One B-rep face of a CAD part: STEP entity #1589.
In plain terms, the planar face has unit normal (1, 0, 0).
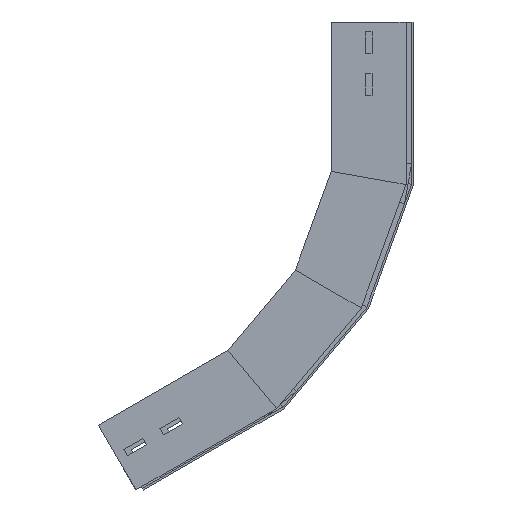
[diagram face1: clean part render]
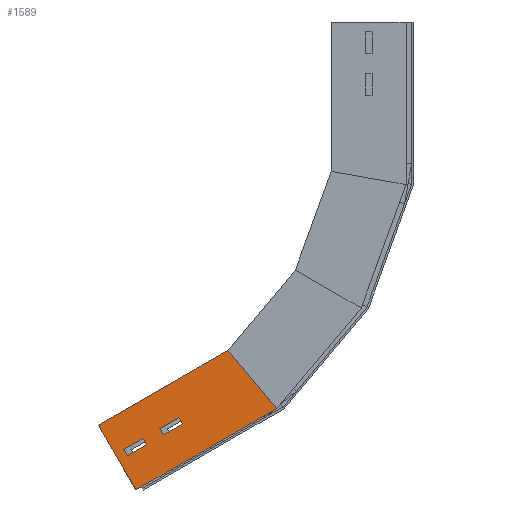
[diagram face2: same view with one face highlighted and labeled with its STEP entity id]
Its self-contained STEP definition (entity closure, numbers rounded to 3 decimals):
#2 = VERTEX_POINT ( 'NONE', #1585 ) ;
#18 = VERTEX_POINT ( 'NONE', #1473 ) ;
#43 = VECTOR ( 'NONE', #1582, 1000. ) ;
#44 = LINE ( 'NONE', #964, #1244 ) ;
#61 = LINE ( 'NONE', #574, #1542 ) ;
#67 = VERTEX_POINT ( 'NONE', #684 ) ;
#82 = LINE ( 'NONE', #198, #102 ) ;
#101 = CARTESIAN_POINT ( 'NONE',  ( 0., 0., 0. ) ) ;
#102 = VECTOR ( 'NONE', #1113, 1000. ) ;
#125 = EDGE_CURVE ( 'NONE', #647, #1373, #150, .T. ) ;
#129 = CARTESIAN_POINT ( 'NONE',  ( 0., 41., -51.505 ) ) ;
#150 = LINE ( 'NONE', #664, #1518 ) ;
#157 = LINE ( 'NONE', #294, #43 ) ;
#158 = VECTOR ( 'NONE', #1565, 1000. ) ;
#182 = CARTESIAN_POINT ( 'NONE',  ( 0., 41., -9.835 ) ) ;
#192 = DIRECTION ( 'NONE',  ( 0., 0., -1. ) ) ;
#196 = CARTESIAN_POINT ( 'NONE',  ( 0., 0., -163. ) ) ;
#198 = CARTESIAN_POINT ( 'NONE',  ( 0., 41., -31.835 ) ) ;
#221 = ORIENTED_EDGE ( 'NONE', *, *, #125, .T. ) ;
#240 = ORIENTED_EDGE ( 'NONE', *, *, #1646, .T. ) ;
#247 = ORIENTED_EDGE ( 'NONE', *, *, #442, .T. ) ;
#248 = EDGE_CURVE ( 'NONE', #67, #1561, #1270, .T. ) ;
#280 = ORIENTED_EDGE ( 'NONE', *, *, #1527, .T. ) ;
#287 = CARTESIAN_POINT ( 'NONE',  ( 0., 0., 0. ) ) ;
#294 = CARTESIAN_POINT ( 'NONE',  ( 0., 41., -51.505 ) ) ;
#314 = AXIS2_PLACEMENT_3D ( 'NONE', #1058, #540, #1076 ) ;
#317 = VERTEX_POINT ( 'NONE', #129 ) ;
#339 = CARTESIAN_POINT ( 'NONE',  ( 0., 41., -73.505 ) ) ;
#348 = DIRECTION ( 'NONE',  ( 0., 1., 0. ) ) ;
#388 = ORIENTED_EDGE ( 'NONE', *, *, #248, .T. ) ;
#400 = EDGE_CURVE ( 'NONE', #18, #814, #1020, .T. ) ;
#413 = EDGE_LOOP ( 'NONE', ( #221, #846, #240, #1072 ) ) ;
#442 = EDGE_CURVE ( 'NONE', #780, #67, #829, .T. ) ;
#476 = VERTEX_POINT ( 'NONE', #196 ) ;
#477 = EDGE_CURVE ( 'NONE', #814, #1327, #61, .T. ) ;
#511 = CARTESIAN_POINT ( 'NONE',  ( 0., 41., -31.835 ) ) ;
#540 = DIRECTION ( 'NONE',  ( -1., 0., 0. ) ) ;
#566 = LINE ( 'NONE', #714, #749 ) ;
#574 = CARTESIAN_POINT ( 'NONE',  ( 0., 75., 0. ) ) ;
#583 = DIRECTION ( 'NONE',  ( 0., 0., -1. ) ) ;
#606 = EDGE_CURVE ( 'NONE', #317, #780, #1043, .T. ) ;
#620 = CARTESIAN_POINT ( 'NONE',  ( 0., 34., -51.505 ) ) ;
#647 = VERTEX_POINT ( 'NONE', #1593 ) ;
#664 = CARTESIAN_POINT ( 'NONE',  ( 0., 41., -9.835 ) ) ;
#681 = FACE_BOUND ( 'NONE', #413, .T. ) ;
#684 = CARTESIAN_POINT ( 'NONE',  ( 0., 34., -73.505 ) ) ;
#714 = CARTESIAN_POINT ( 'NONE',  ( 0., 27.875, -158.085 ) ) ;
#749 = VECTOR ( 'NONE', #1112, 1000. ) ;
#753 = VECTOR ( 'NONE', #348, 1000. ) ;
#780 = VERTEX_POINT ( 'NONE', #339 ) ;
#798 = EDGE_CURVE ( 'NONE', #2, #647, #44, .T. ) ;
#814 = VERTEX_POINT ( 'NONE', #1372 ) ;
#817 = FACE_OUTER_BOUND ( 'NONE', #1051, .T. ) ;
#829 = LINE ( 'NONE', #1221, #1143 ) ;
#846 = ORIENTED_EDGE ( 'NONE', *, *, #869, .T. ) ;
#869 = EDGE_CURVE ( 'NONE', #1373, #926, #984, .T. ) ;
#916 = CARTESIAN_POINT ( 'NONE',  ( 0., 41., -51.505 ) ) ;
#926 = VERTEX_POINT ( 'NONE', #511 ) ;
#964 = CARTESIAN_POINT ( 'NONE',  ( 0., 34., -9.835 ) ) ;
#984 = LINE ( 'NONE', #182, #1570 ) ;
#1020 = LINE ( 'NONE', #101, #753 ) ;
#1043 = LINE ( 'NONE', #916, #1607 ) ;
#1049 = DIRECTION ( 'NONE',  ( 0., 0., -1. ) ) ;
#1051 = EDGE_LOOP ( 'NONE', ( #1305, #1520, #1588, #1184 ) ) ;
#1058 = CARTESIAN_POINT ( 'NONE',  ( 0., 0., 0. ) ) ;
#1060 = VECTOR ( 'NONE', #1049, 1000. ) ;
#1072 = ORIENTED_EDGE ( 'NONE', *, *, #798, .T. ) ;
#1076 = DIRECTION ( 'NONE',  ( 0., 0., 1. ) ) ;
#1101 = DIRECTION ( 'NONE',  ( 0., -1., 0. ) ) ;
#1112 = DIRECTION ( 'NONE',  ( 0., -0.985, -0.174 ) ) ;
#1113 = DIRECTION ( 'NONE',  ( 0., -1., 0. ) ) ;
#1137 = CARTESIAN_POINT ( 'NONE',  ( 0., 41., -9.835 ) ) ;
#1143 = VECTOR ( 'NONE', #1101, 1000. ) ;
#1163 = EDGE_CURVE ( 'NONE', #1327, #476, #566, .T. ) ;
#1177 = ORIENTED_EDGE ( 'NONE', *, *, #606, .T. ) ;
#1184 = ORIENTED_EDGE ( 'NONE', *, *, #1163, .F. ) ;
#1189 = DIRECTION ( 'NONE',  ( 0., 0., 1. ) ) ;
#1194 = DIRECTION ( 'NONE',  ( 0., 1., 0. ) ) ;
#1204 = CARTESIAN_POINT ( 'NONE',  ( 0., 34., -51.505 ) ) ;
#1221 = CARTESIAN_POINT ( 'NONE',  ( 0., 41., -73.505 ) ) ;
#1244 = VECTOR ( 'NONE', #1189, 1000. ) ;
#1260 = CARTESIAN_POINT ( 'NONE',  ( 0., 75., -149.775 ) ) ;
#1270 = LINE ( 'NONE', #620, #158 ) ;
#1289 = DIRECTION ( 'NONE',  ( 0., 0., -1. ) ) ;
#1305 = ORIENTED_EDGE ( 'NONE', *, *, #477, .F. ) ;
#1315 = LINE ( 'NONE', #287, #1060 ) ;
#1327 = VERTEX_POINT ( 'NONE', #1260 ) ;
#1336 = FACE_BOUND ( 'NONE', #1640, .T. ) ;
#1372 = CARTESIAN_POINT ( 'NONE',  ( 0., 75., 0. ) ) ;
#1373 = VERTEX_POINT ( 'NONE', #1137 ) ;
#1451 = PLANE ( 'NONE',  #314 ) ;
#1473 = CARTESIAN_POINT ( 'NONE',  ( 0., 0., 0. ) ) ;
#1493 = EDGE_CURVE ( 'NONE', #18, #476, #1315, .T. ) ;
#1518 = VECTOR ( 'NONE', #1194, 1000. ) ;
#1520 = ORIENTED_EDGE ( 'NONE', *, *, #400, .F. ) ;
#1527 = EDGE_CURVE ( 'NONE', #1561, #317, #157, .T. ) ;
#1542 = VECTOR ( 'NONE', #583, 1000. ) ;
#1561 = VERTEX_POINT ( 'NONE', #1204 ) ;
#1565 = DIRECTION ( 'NONE',  ( 0., 0., 1. ) ) ;
#1570 = VECTOR ( 'NONE', #192, 1000. ) ;
#1582 = DIRECTION ( 'NONE',  ( 0., 1., 0. ) ) ;
#1585 = CARTESIAN_POINT ( 'NONE',  ( 0., 34., -31.835 ) ) ;
#1588 = ORIENTED_EDGE ( 'NONE', *, *, #1493, .T. ) ;
#1589 = ADVANCED_FACE ( 'NONE', ( #1336, #817, #681 ), #1451, .F. ) ;
#1593 = CARTESIAN_POINT ( 'NONE',  ( 0., 34., -9.835 ) ) ;
#1607 = VECTOR ( 'NONE', #1289, 1000. ) ;
#1640 = EDGE_LOOP ( 'NONE', ( #280, #1177, #247, #388 ) ) ;
#1646 = EDGE_CURVE ( 'NONE', #926, #2, #82, .T. ) ;
